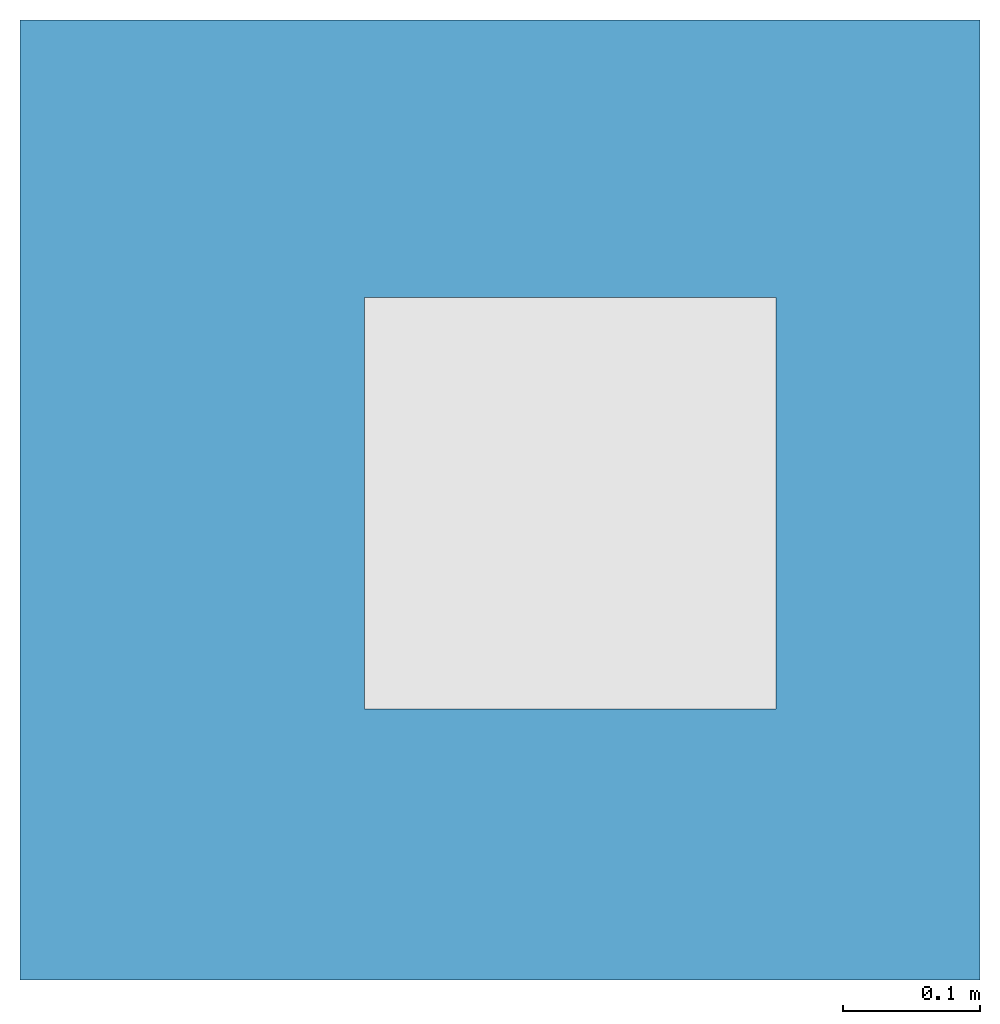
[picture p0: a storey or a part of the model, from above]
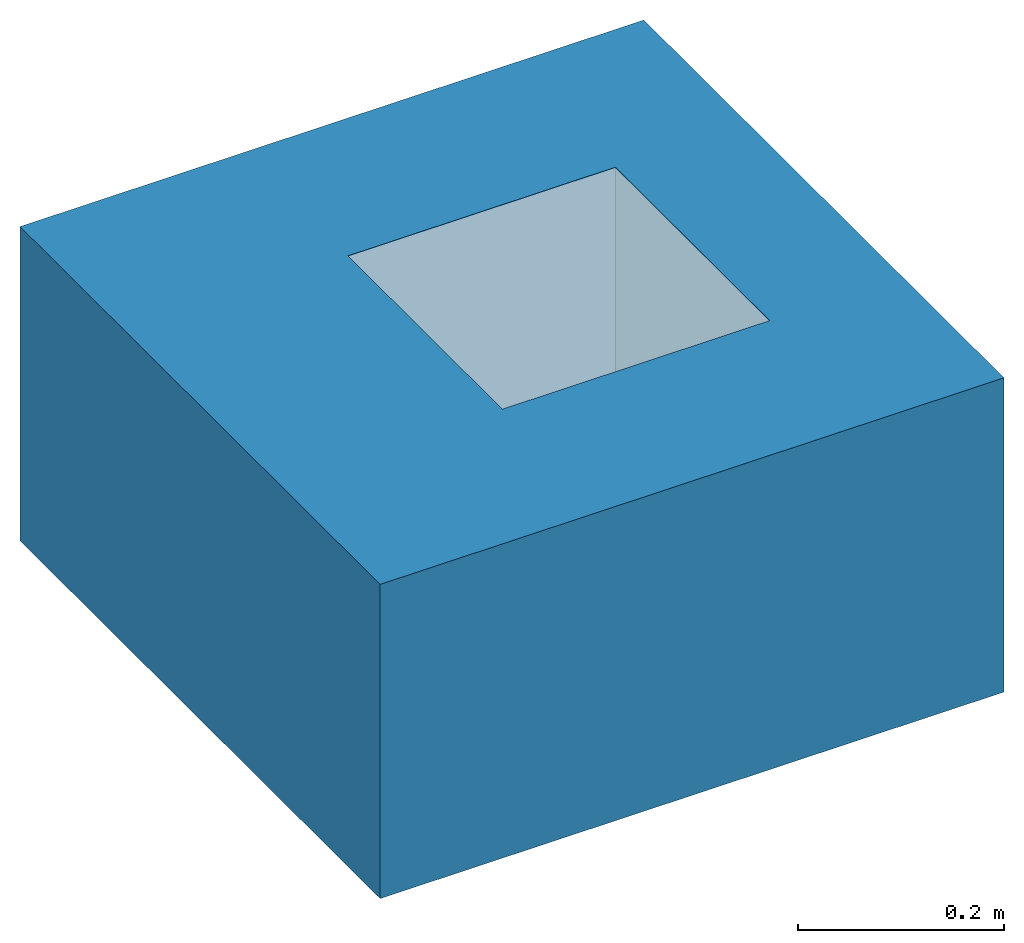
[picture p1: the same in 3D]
Properties of the parts of a building model (IFC2X3)

# File
Description: ViewDefinition [CoordinationView]
File name: Project Number
Time: 2014-10-13T17:57:19
Written by: The EXPRESS Data Manager Version 5.01.0100.02.64mod : 6 Jun 2012
Made in: 20130308_1515(x64) - Exporter 2014.0.2013.0308 - Default UI
Comment: STEP Physical File produced by: The EXPRESS Data Manager Version 5.01.0100.02.64mod : 6 Jun 2012 * Module: EDMstepFileFactory/EDMstandAlone * Creation date: Mon Oct 13 17:57:19 2014 * Host: IN-BLR-PC-0012 * Database: C:\Users\pponnur\AppData\Local\Temp\{A76530A3-58D7-48B1-824B-770E1A55FC66}\ifc * Database version: 5507 * Database creation date: Mon Oct 13 17:57:18 2014 * Schema: IFC2X3 * Model: DataRepository.ifc * Model creation date: Mon Oct 13 17:57:18 2014 * Header model: DataRepository.ifc_HeaderModel * Header model creation date: Mon Oct 13 17:57:18 2014 * EDMuser: sdai-user * EDMgroup: sdai-group * License ID and type: 5605 : Permanent license. Expiry date: * EDMstepFileFactory options: 020000

# IfcProject, Project Number
LongName: Project Name; Phase: Project Status

# IfcSite, Default
RefLatitude: 42, 21, 30, 344238; RefLongitude: -71, -3, -35, -194702; RefElevation: 0 mm

# IfcBuilding
Pset_BuildingCommon - NumberOfStoreys: 1
Other - Project Issue Date: Issue Date; Project Status: Project Status; Client Name: Owner; Project Number: Project Number; Project Address: Enter address here; Project Name: Project Name

# IfcBuildingStorey, Level 1
LongName: Level 1; Elevation: 0 mm
Graphics - Line Weight: 1; Symbol: Level Head - Circle: Level Head - Circle; Symbol at End 2 Default: yes; Line Pattern: Grid Line 1/2"; Symbol at End 1 Default: no; Color: 0
Constraints - Elevation Base: Project Base Point; Elevation: 0 mm
Identity Data - Structural: no; Building Story: yes; Name: Level 1
Dimensions - Computation Height: 0 mm

# IfcFlowTerminal: 408061 Body / 408228 Top - 110mm Dia Outlet, ACO BD Gully 218 Telescopic - Square Top - Vertical Outlet with Location Flange - 300x300:408061 Body / 408228 Top - 110mm Dia Outlet:187132
In: Level 1
Material: Stainless Steel AISI 304, Rubber, Nitrile
Mechanical - System Classification: Sanitary
Construction - 408036 - 268 x 268mm - Quadrato Grating - Brushed - Stainless steel 304: no; 408041 - 268 x 268mm - Arla Grating - Slip Resistant - Stainless Steel 304: no; 408034 - 268 x 268mm - Mesh Grating - Slip Resistant - Stainless Steel 304: no; 408042 - 268 x 268mm - Volcano Grating - Slip Resistant - Stainless Steel 304: no; 408045 - 268 x 268mm - Ladder Grating - Plain - Stainless Steel 304: no; 408220 - Foul Air Trap & 408221 - Foul Air Trap Support Ring: yes; 408039 - 268 x 268mm - Slot Cover - Plain - Stainless Steel 304: no; 408040 - 268 x 268mm - HeelSafe Grating - Brushed - Stainless Steel 304: no; 408035 - 268 x 268mm - Mesh Grating - Plain - Stainless Steel 304: no; 408222 - Silt Basket: yes; 408038 - 268 x 268mm - Ladder Grating - Plain - Stainless Steel 304: no; 408037 - 268 x 268mm - Ladder Grating - Slip Resistant - Stainless steel 304: no; 110 mm Dia Outlet: yes; 160 mm Dia Outlet: no
Other - Raising Piece Height: 500 mm; Floor Void Depth: -336 mm; Floor To Gully Height: 68 mm; Raising Piece Detail: no; Raising Piece: no; Floor Top To First Layer: 68 mm; Gully Outlet Radius: 55 mm; Gully Outlet Depth: 98 mm
Model Properties - Raising Piece Product Code 408209: NA; Grating Product Code 408038: Load Class M125 (EN 1253) - Ladder Grating -Plain - Stainless steel 1.4301 (EN 10088) - 268 x 268 x 30mm; Product Code 408222: Silt Basket - Stainless Steel 304; Grating Product Code 408036: Load Class L15 (EN 1253) - Quadrato Grating - Brushed - Stainless steel 1.4301 (EN 10088) - 268 x 268 x 30mm; Grating Product Code 408039: Load Class M125 (EN 1253) - Slot Cover - Plain - Stainless steel 1.4301 (EN 10088) - 268 x 268 x 30mm; Grating Product Code 408037: Load Class M125 (EN 1253) - Ladder Grating - Slip Resistant - Stainless steel 1.4301 (EN 10088) - 268 x 268 x 30mm; Grating Product Code 408041: Load Class L15 (EN 1253) - Arla Grating - Slip Resistant - Stainless steel 1.4301 (EN 10088) - 268 x 268 x 30mm; Grating Product Code 408045: Load Class C250 (EN 1253) - Ladder Grating - Plain - Stainless steel 1.4301 (EN 10088) - 268 x 268 x 30mm; Product Code 408221: Foul Air Trap Support Ring - Nitrile; Grating Product Code 408034: Load Class L15 (EN 1253) - Mesh Grating - Slip Resistant - Stainless steel 1.4301 (EN 10088) - 268 x 268 x 30mm; Grating Product Code 408040: Load Class L15 (EN 1253) - Heelsafe Grating - Brushed - Stainless steel 1.4301 (EN 10088) - 268 x 268 x 30mm; Grating Product Code 408042: Load Class M125 (EN 1253) - Volcano Grating - Slip Resistant - Stainless steel 1.4301 (EN 10088) - 268 x 268 x 30mm; Product Code 408220: Foul Air Trap - Stainless Steel 304; Product Code 408225: Friction Ring Installation Set - Nitrile; Grating Product Code 408035: Load Class L15 (EN 1253) - Mesh Grating – Plain - Stainless steel 1.4301 (EN 10088) - 268 x 268 x 30mm
Identity Data - Mark: 1; Website: www.acobd.com; Watermarked By: www.acobd.com; Fax: +44 (0)1462 851490; E-mail Technical: abdtechnical@aco.co.uk; E-mail Sales: abdcommercial@aco.co.uk; Water Mark 1: This file is the property of ACO Technologies PLC; Address: ACO Business Centre, Caxton Road, Bedford, MK41 0LF; Water Marked With: BIM Manager Premium Suite; Manufacturer: ACO Building Drainage; Telephone: +44 (0)1462 816666; Water Mark 2: This file is water marked and users are prohibited to reproduce, adapt, distribute this information
Phasing - Phase Created: New Construction
Constraints - Level: Level: Level 1
Pset_ManufacturerTypeInformation - Manufacturer: ACO Building Drainage
General - Foul Air Trap Seal Recycled Material Content: 0%; Gully Flange Type: Location; Load Class: A15 - C250 (EN 1253); NBS Specification: R11 ABOVE GROUND FOUL DRAINAGE SYSTEMS : Clause 315; Gully top Grate size (mm): 300 x 300; Product Standard: EN 1253; Foul Air Trap Seal Recyclable: Fully recyclable; Foul Air Trap Seal Material: NBR; Outlet Diameter (mm): 110; Flow Rate (l/s): 5.0 - 6.3 l/s; Gully Colour: passivated stainless steel surface ( matt grey); Gully Recyclable: Fully recyclable Fully recyclable; Gully Top Product Code: 408228; Maintenance guidelines: http://issuu.com/acobuildingdrainage/docs/120820112708-138bdc871b784edfa2b6b8197acfd881?e=0; Installation guidelines: http://issuu.com/acobuildingdrainage/docs/120820112708-138bdc871b784edfa2b6b8197acfd881?e=0; Gully Top Product Description: ACO Gully 218 Telescopic Top for Concrete, Tiled or Resin Floor; Gully Material: Stainless Steel Grade 304 (EN 1253); Product Type: Point Drainage; Gully Product Description: ACO Gully 218 Telescopic Flange Type DN110 Vertical with Foul Air Trap; Price: POA - contact ACO; Gully Top Size (mm): 242mm Diameter; Foul Air Trap Seal Colour: Black; Gully Recycled Material Content: 20 - 30 %; Product Range: ACO Gully 218; Gully Product Code: 408061
Materials and Finishes - Material: Stainless Steel AISI 304

# IfcSlab: Floor:Generic - 12", Floor:Generic - 12":184145
In: Level 1
PredefinedType: FLOOR; Material: Plywood, Sheathing 68 mm, Default Floor 304.8 mm
Constraints - Related to Mass: no; Height Offset From Level: 0 mm; Room Bounding: yes; Level: Level: Level 1
Dimensions - Area: 5.27432 ft2; Thickness: 372.8 mm; Volume: 5.38309 ft3; Perimeter: 2800 mm
Structural - Enable Analytical Model: no; Structural: no
Phasing - Phase Created: New Construction
Pset_SlabCommon - Reference: Generic - 12"; IsExternal: no; LoadBearing: yes; ThermalTransmittance: 1.55882 kg/K/s3; PitchAngle: 0 deg
Identity Data - Assembly Description: Floor Construction; Assembly Code: B1010
Analytical Properties - Heat Transfer Coefficient (U): 1.55882; Roughness: 3; Thermal Resistance (R): 0.641509; Absorptance: 0.7; Thermal mass: 53301.1
Construction - Function: Interior; Default Thickness: 372.8 mm
Graphics - Coarse Scale Fill Color: 0
